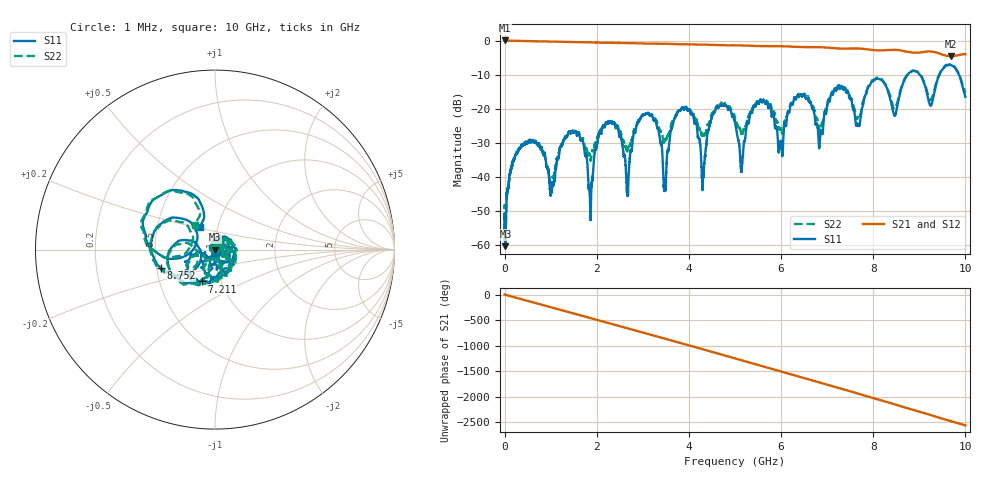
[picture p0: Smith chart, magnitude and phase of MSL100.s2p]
! 3/21/2017 9:29:37 AM
! F:\HUSERTL_20170321\MSL100.S2P
! CHANNEL.1
! TR.MEASUREMENT
! CORRECTED.DATA
# GHZ S RI R 50.0
! FREQ.GHZ  S11RE  S11IM  S21RE  S21IM  S12RE  S12IM  S22RE  S22IM
!; PortSelection: Port_13
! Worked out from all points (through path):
!   10000 points, 1 MHz to 10 GHz, reference 50 ohm
!   highest |S21| = 0.03 dB at 10 MHz (marker M1); lowest = -4.6 dB at 9.678 GHz (marker M2)
!   group delay of S21, straight-line fit = 709 ps
!   lowest |S11| = -60.3 dB at 19 MHz (marker M3), VSWR 1.00, Z = 50 - j0.0924 ohm
!   |S11| at or under -10 dB: start of sweep to 8.746 GHz; 9.011 GHz to 9.438 GHz (427 MHz wide, 4.63 % of centre); 9.861 GHz to end of sweep
!   |S22| runs from -58.9 to -6.9 dB; largest |S21 - S12| = 0.043
!   S11 on the Smith chart (normalised r, x): 1 MHz: 1.01, +0.00; 7.211 GHz: 0.81, -0.30; 8.752 GHz: 0.53, -0.12; 10 GHz: 0.81, +0.20
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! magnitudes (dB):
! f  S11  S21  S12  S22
! 1 MHz  -50.9  0.0  0.0  -53.4
! 10 MHz  -56.6  0.0  0.0  -52.6
! 19 MHz  -60.3  0.0  0.0  -55.2
! 373 MHz  -30.5  -0.1  -0.1  -30.8
! 1.025 GHz  -43.6  -0.3  -0.3  -42.6
! 1.668 GHz  -29.3  -0.5  -0.5  -28.7
! 1.863 GHz  -50.5  -0.5  -0.5  -35.0
! 2.175 GHz  -25.4  -0.6  -0.6  -24.8
! 2.665 GHz  -44.9  -0.7  -0.8  -31.9
! 2.943 GHz  -22.8  -0.8  -0.8  -22.9
! 3.334 GHz  -25.9  -0.9  -0.9  -24.8
! 3.477 GHz  -42.7  -0.9  -0.9  -29.4
! 3.816 GHz  -20.4  -1.1  -1.1  -20.3
! 4.308 GHz  -40.1  -1.2  -1.2  -27.4
! 4.571 GHz  -20.6  -1.3  -1.3  -20.3
! 5.001 GHz  -24.1  -1.4  -1.4  -22.4
! 6.667 GHz  -19.6  -1.9  -2.0  -18.3
! 7.211 GHz  -14.3  -2.3  -2.3  -14.2
! 8.334 GHz  -15.5  -2.8  -2.8  -15.0
! 8.752 GHz  -9.9  -3.3  -3.3  -9.8
! 9.678 GHz  -7.1  -4.6  -4.6  -6.9
! 10 GHz  -16.5  -4.0  -4.0  -15.3
